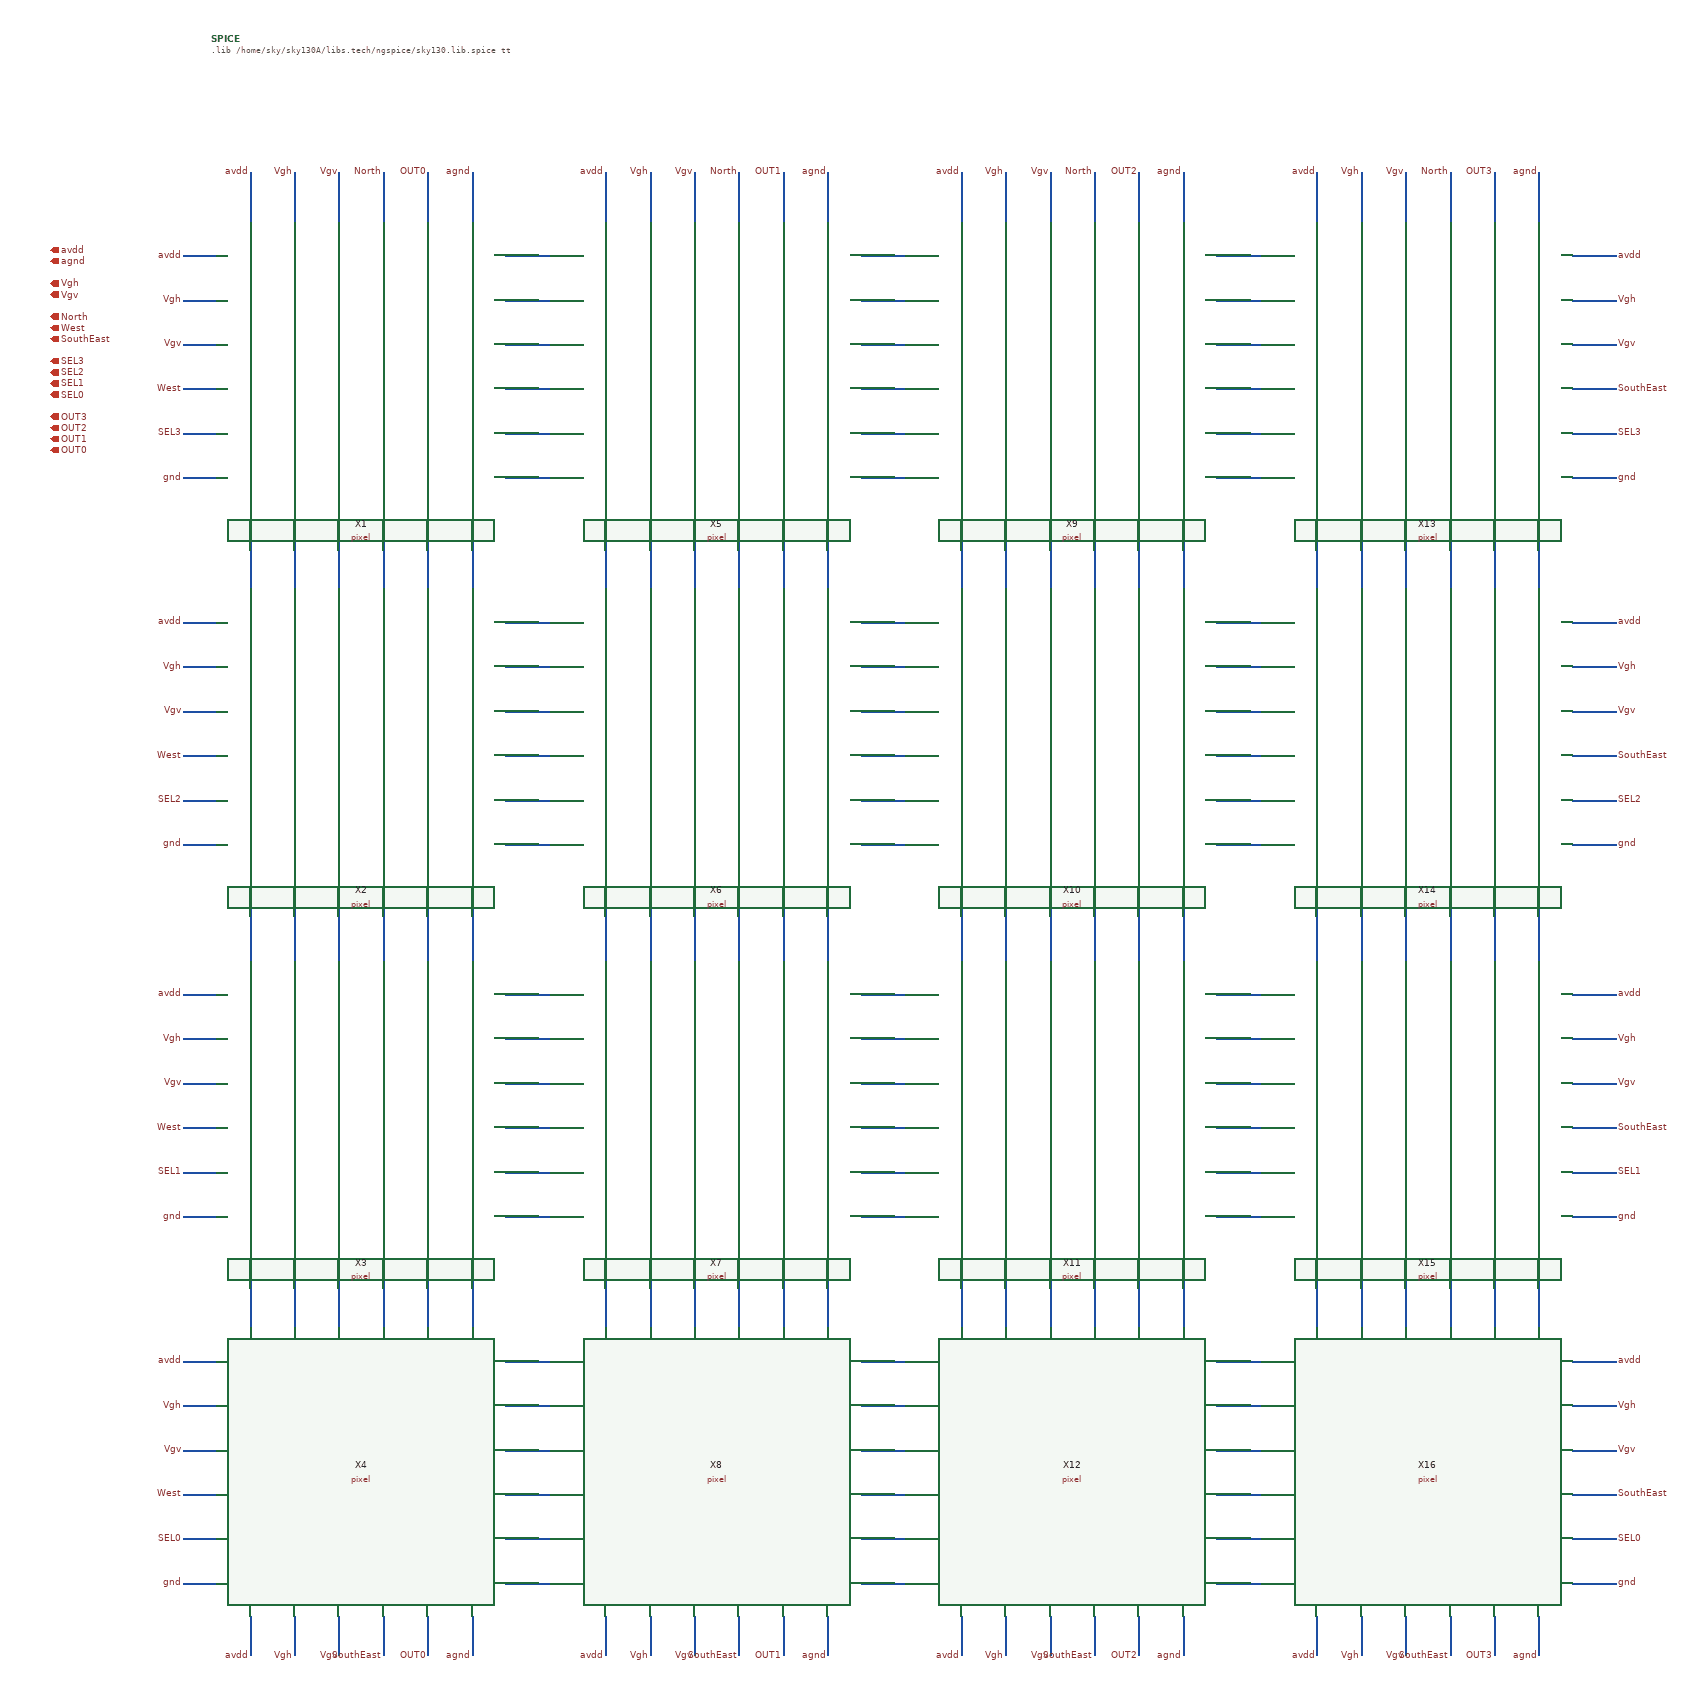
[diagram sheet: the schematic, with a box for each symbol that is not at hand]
v {xschem version=2.9.9 file_version=1.2 }
G {}
K {}
V {}
S {}
E {}
N -1280 -1190 -1220 -1190 { lab=avdd}
N -1280 -1110 -1220 -1110 { lab=Vgh}
N -1280 -1030 -1220 -1030 { lab=Vgv}
N -1160 -1340 -1160 -1250 { lab=avdd}
N -1080 -1340 -1080 -1250 { lab=Vgh}
N -1000 -1340 -1000 -1250 { lab=Vgv}
N -920 -1340 -920 -1250 { lab=North}
N -840 -1340 -840 -1250 { lab=OUT0}
N -760 -1340 -760 -1250 { lab=agnd}
N -700 -1190 -620 -1190 { lab=#net1}
N -700 -1110 -620 -1110 { lab=#net2}
N -700 -1030 -620 -1030 { lab=#net3}
N -700 -950 -620 -950 { lab=#net4}
N -700 -870 -620 -870 { lab=#net5}
N -700 -790 -620 -790 { lab=#net6}
N -760 -730 -760 -660 { lab=#net7}
N -840 -730 -840 -660 { lab=#net8}
N -920 -730 -920 -660 { lab=#net9}
N -1000 -730 -1000 -660 { lab=#net10}
N -1080 -730 -1080 -660 { lab=#net11}
N -1160 -730 -1160 -660 { lab=#net12}
N -1280 -950 -1220 -950 { lab=West}
N -1280 -870 -1220 -870 { lab=SEL3}
N -1280 -790 -1220 -790 { lab=gnd}
N -1280 -530 -1220 -530 { lab=avdd}
N -1280 -450 -1220 -450 { lab=Vgh}
N -1280 -370 -1220 -370 { lab=Vgv}
N -1160 -680 -1160 -590 { lab=#net12}
N -1080 -680 -1080 -590 { lab=#net11}
N -1000 -680 -1000 -590 { lab=#net10}
N -920 -680 -920 -590 { lab=#net9}
N -840 -680 -840 -590 { lab=#net8}
N -760 -680 -760 -590 { lab=#net7}
N -700 -530 -620 -530 { lab=#net13}
N -700 -450 -620 -450 { lab=#net14}
N -700 -370 -620 -370 { lab=#net15}
N -700 -290 -620 -290 { lab=#net16}
N -700 -210 -620 -210 { lab=#net17}
N -700 -130 -620 -130 { lab=#net18}
N -760 -70 -760 0 { lab=#net19}
N -840 -70 -840 0 { lab=#net20}
N -920 -70 -920 0 { lab=#net21}
N -1000 -70 -1000 0 { lab=#net22}
N -1080 -70 -1080 0 { lab=#net23}
N -1160 -70 -1160 0 { lab=#net24}
N -1280 -290 -1220 -290 { lab=West}
N -1280 -210 -1220 -210 { lab=SEL2}
N -1280 -130 -1220 -130 { lab=gnd}
N -1280 140 -1220 140 { lab=avdd}
N -1280 220 -1220 220 { lab=Vgh}
N -1280 300 -1220 300 { lab=Vgv}
N -1160 -10 -1160 80 { lab=#net24}
N -1080 -10 -1080 80 { lab=#net23}
N -1000 -10 -1000 80 { lab=#net22}
N -920 -10 -920 80 { lab=#net21}
N -840 -10 -840 80 { lab=#net20}
N -760 -10 -760 80 { lab=#net19}
N -700 140 -620 140 { lab=#net25}
N -700 220 -620 220 { lab=#net26}
N -700 300 -620 300 { lab=#net27}
N -700 380 -620 380 { lab=#net28}
N -700 460 -620 460 { lab=#net29}
N -700 540 -620 540 { lab=#net30}
N -760 600 -760 670 { lab=#net31}
N -840 600 -840 670 { lab=#net32}
N -920 600 -920 670 { lab=#net33}
N -1000 600 -1000 670 { lab=#net34}
N -1080 600 -1080 670 { lab=#net35}
N -1160 600 -1160 670 { lab=#net36}
N -1280 380 -1220 380 { lab=West}
N -1280 460 -1220 460 { lab=SEL1}
N -1280 540 -1220 540 { lab=gnd}
N -1280 800 -1220 800 { lab=avdd}
N -1280 880 -1220 880 { lab=Vgh}
N -1280 960 -1220 960 { lab=Vgv}
N -1160 650 -1160 740 { lab=#net36}
N -1080 650 -1080 740 { lab=#net35}
N -1000 650 -1000 740 { lab=#net34}
N -920 650 -920 740 { lab=#net33}
N -840 650 -840 740 { lab=#net32}
N -760 650 -760 740 { lab=#net31}
N -700 800 -620 800 { lab=#net37}
N -700 880 -620 880 { lab=#net38}
N -700 960 -620 960 { lab=#net39}
N -700 1040 -620 1040 { lab=#net40}
N -700 1120 -620 1120 { lab=#net41}
N -700 1200 -620 1200 { lab=#net42}
N -760 1260 -760 1330 { lab=agnd}
N -840 1260 -840 1330 { lab=OUT0}
N -920 1260 -920 1330 { lab=SouthEast}
N -1000 1260 -1000 1330 { lab=Vgv}
N -1080 1260 -1080 1330 { lab=Vgh}
N -1160 1260 -1160 1330 { lab=avdd}
N -1280 1040 -1220 1040 { lab=West}
N -1280 1120 -1220 1120 { lab=SEL0}
N -1280 1200 -1220 1200 { lab=gnd}
N -640 -1190 -580 -1190 { lab=#net1}
N -640 -1110 -580 -1110 { lab=#net2}
N -640 -1030 -580 -1030 { lab=#net3}
N -520 -1340 -520 -1250 { lab=avdd}
N -440 -1340 -440 -1250 { lab=Vgh}
N -360 -1340 -360 -1250 { lab=Vgv}
N -280 -1340 -280 -1250 { lab=North}
N -200 -1340 -200 -1250 { lab=OUT1}
N -120 -1340 -120 -1250 { lab=agnd}
N -60 -1190 20 -1190 { lab=#net43}
N -60 -1110 20 -1110 { lab=#net44}
N -60 -1030 20 -1030 { lab=#net45}
N -60 -950 20 -950 { lab=#net46}
N -60 -870 20 -870 { lab=#net47}
N -60 -790 20 -790 { lab=#net48}
N -120 -730 -120 -660 { lab=#net49}
N -200 -730 -200 -660 { lab=#net50}
N -280 -730 -280 -660 { lab=#net51}
N -360 -730 -360 -660 { lab=#net52}
N -440 -730 -440 -660 { lab=#net53}
N -520 -730 -520 -660 { lab=#net54}
N -640 -950 -580 -950 { lab=#net4}
N -640 -870 -580 -870 { lab=#net5}
N -640 -790 -580 -790 { lab=#net6}
N -640 -530 -580 -530 { lab=#net13}
N -640 -450 -580 -450 { lab=#net14}
N -640 -370 -580 -370 { lab=#net15}
N -520 -680 -520 -590 { lab=#net54}
N -440 -680 -440 -590 { lab=#net53}
N -360 -680 -360 -590 { lab=#net52}
N -280 -680 -280 -590 { lab=#net51}
N -200 -680 -200 -590 { lab=#net50}
N -120 -680 -120 -590 { lab=#net49}
N -60 -530 20 -530 { lab=#net55}
N -60 -450 20 -450 { lab=#net56}
N -60 -370 20 -370 { lab=#net57}
N -60 -290 20 -290 { lab=#net58}
N -60 -210 20 -210 { lab=#net59}
N -60 -130 20 -130 { lab=#net60}
N -120 -70 -120 0 { lab=#net61}
N -200 -70 -200 0 { lab=#net62}
N -280 -70 -280 0 { lab=#net63}
N -360 -70 -360 0 { lab=#net64}
N -440 -70 -440 0 { lab=#net65}
N -520 -70 -520 0 { lab=#net66}
N -640 -290 -580 -290 { lab=#net16}
N -640 -210 -580 -210 { lab=#net17}
N -640 -130 -580 -130 { lab=#net18}
N -640 140 -580 140 { lab=#net25}
N -640 220 -580 220 { lab=#net26}
N -640 300 -580 300 { lab=#net27}
N -520 -10 -520 80 { lab=#net66}
N -440 -10 -440 80 { lab=#net65}
N -360 -10 -360 80 { lab=#net64}
N -280 -10 -280 80 { lab=#net63}
N -200 -10 -200 80 { lab=#net62}
N -120 -10 -120 80 { lab=#net61}
N -60 140 20 140 { lab=#net67}
N -60 220 20 220 { lab=#net68}
N -60 300 20 300 { lab=#net69}
N -60 380 20 380 { lab=#net70}
N -60 460 20 460 { lab=#net71}
N -60 540 20 540 { lab=#net72}
N -120 600 -120 670 { lab=#net73}
N -200 600 -200 670 { lab=#net74}
N -280 600 -280 670 { lab=#net75}
N -360 600 -360 670 { lab=#net76}
N -440 600 -440 670 { lab=#net77}
N -520 600 -520 670 { lab=#net78}
N -640 380 -580 380 { lab=#net28}
N -640 460 -580 460 { lab=#net29}
N -640 540 -580 540 { lab=#net30}
N -640 800 -580 800 { lab=#net37}
N -640 880 -580 880 { lab=#net38}
N -640 960 -580 960 { lab=#net39}
N -520 650 -520 740 { lab=#net78}
N -440 650 -440 740 { lab=#net77}
N -360 650 -360 740 { lab=#net76}
N -280 650 -280 740 { lab=#net75}
N -200 650 -200 740 { lab=#net74}
N -120 650 -120 740 { lab=#net73}
N -60 800 20 800 { lab=#net79}
N -60 880 20 880 { lab=#net80}
N -60 960 20 960 { lab=#net81}
N -60 1040 20 1040 { lab=#net82}
N -60 1120 20 1120 { lab=#net83}
N -60 1200 20 1200 { lab=#net84}
N -120 1260 -120 1330 { lab=agnd}
N -200 1260 -200 1330 { lab=OUT1}
N -280 1260 -280 1330 { lab=SouthEast}
N -360 1260 -360 1330 { lab=Vgv}
N -440 1260 -440 1330 { lab=Vgh}
N -520 1260 -520 1330 { lab=avdd}
N -640 1040 -580 1040 { lab=#net40}
N -640 1120 -580 1120 { lab=#net41}
N -640 1200 -580 1200 { lab=#net42}
N 0 -1190 60 -1190 { lab=#net43}
N 0 -1110 60 -1110 { lab=#net44}
N 0 -1030 60 -1030 { lab=#net45}
N 120 -1340 120 -1250 { lab=avdd}
N 200 -1340 200 -1250 { lab=Vgh}
N 280 -1340 280 -1250 { lab=Vgv}
N 360 -1340 360 -1250 { lab=North}
N 440 -1340 440 -1250 { lab=OUT2}
N 520 -1340 520 -1250 { lab=agnd}
N 580 -1190 660 -1190 { lab=#net85}
N 580 -1110 660 -1110 { lab=#net86}
N 580 -1030 660 -1030 { lab=#net87}
N 580 -950 660 -950 { lab=#net88}
N 580 -870 660 -870 { lab=#net89}
N 580 -790 660 -790 { lab=#net90}
N 520 -730 520 -660 { lab=#net91}
N 440 -730 440 -660 { lab=#net92}
N 360 -730 360 -660 { lab=#net93}
N 280 -730 280 -660 { lab=#net94}
N 200 -730 200 -660 { lab=#net95}
N 120 -730 120 -660 { lab=#net96}
N 0 -950 60 -950 { lab=#net46}
N 0 -870 60 -870 { lab=#net47}
N 0 -790 60 -790 { lab=#net48}
N 0 -530 60 -530 { lab=#net55}
N 0 -450 60 -450 { lab=#net56}
N 0 -370 60 -370 { lab=#net57}
N 120 -680 120 -590 { lab=#net96}
N 200 -680 200 -590 { lab=#net95}
N 280 -680 280 -590 { lab=#net94}
N 360 -680 360 -590 { lab=#net93}
N 440 -680 440 -590 { lab=#net92}
N 520 -680 520 -590 { lab=#net91}
N 580 -530 660 -530 { lab=#net97}
N 580 -450 660 -450 { lab=#net98}
N 580 -370 660 -370 { lab=#net99}
N 580 -290 660 -290 { lab=#net100}
N 580 -210 660 -210 { lab=#net101}
N 580 -130 660 -130 { lab=#net102}
N 520 -70 520 0 { lab=#net103}
N 440 -70 440 0 { lab=#net104}
N 360 -70 360 0 { lab=#net105}
N 280 -70 280 0 { lab=#net106}
N 200 -70 200 0 { lab=#net107}
N 120 -70 120 0 { lab=#net108}
N 0 -290 60 -290 { lab=#net58}
N 0 -210 60 -210 { lab=#net59}
N 0 -130 60 -130 { lab=#net60}
N 0 140 60 140 { lab=#net67}
N 0 220 60 220 { lab=#net68}
N 0 300 60 300 { lab=#net69}
N 120 -10 120 80 { lab=#net108}
N 200 -10 200 80 { lab=#net107}
N 280 -10 280 80 { lab=#net106}
N 360 -10 360 80 { lab=#net105}
N 440 -10 440 80 { lab=#net104}
N 520 -10 520 80 { lab=#net103}
N 580 140 660 140 { lab=#net109}
N 580 220 660 220 { lab=#net110}
N 580 300 660 300 { lab=#net111}
N 580 380 660 380 { lab=#net112}
N 580 460 660 460 { lab=#net113}
N 580 540 660 540 { lab=#net114}
N 520 600 520 670 { lab=#net115}
N 440 600 440 670 { lab=#net116}
N 360 600 360 670 { lab=#net117}
N 280 600 280 670 { lab=#net118}
N 200 600 200 670 { lab=#net119}
N 120 600 120 670 { lab=#net120}
N 0 380 60 380 { lab=#net70}
N 0 460 60 460 { lab=#net71}
N 0 540 60 540 { lab=#net72}
N 0 800 60 800 { lab=#net79}
N 0 880 60 880 { lab=#net80}
N 0 960 60 960 { lab=#net81}
N 120 650 120 740 { lab=#net120}
N 200 650 200 740 { lab=#net119}
N 280 650 280 740 { lab=#net118}
N 360 650 360 740 { lab=#net117}
N 440 650 440 740 { lab=#net116}
N 520 650 520 740 { lab=#net115}
N 580 800 660 800 { lab=#net121}
N 580 880 660 880 { lab=#net122}
N 580 960 660 960 { lab=#net123}
N 580 1040 660 1040 { lab=#net124}
N 580 1120 660 1120 { lab=#net125}
N 580 1200 660 1200 { lab=#net126}
N 520 1260 520 1330 { lab=agnd}
N 440 1260 440 1330 { lab=OUT2}
N 360 1260 360 1330 { lab=SouthEast}
N 280 1260 280 1330 { lab=Vgv}
N 200 1260 200 1330 { lab=Vgh}
N 120 1260 120 1330 { lab=avdd}
N 0 1040 60 1040 { lab=#net82}
N 0 1120 60 1120 { lab=#net83}
N 0 1200 60 1200 { lab=#net84}
N 640 -1190 700 -1190 { lab=#net85}
N 640 -1110 700 -1110 { lab=#net86}
N 640 -1030 700 -1030 { lab=#net87}
N 760 -1340 760 -1250 { lab=avdd}
N 840 -1340 840 -1250 { lab=Vgh}
N 920 -1340 920 -1250 { lab=Vgv}
N 1000 -1340 1000 -1250 { lab=North}
N 1080 -1340 1080 -1250 { lab=OUT3}
N 1160 -1340 1160 -1250 { lab=agnd}
N 1220 -1190 1300 -1190 { lab=avdd}
N 1220 -1110 1300 -1110 { lab=Vgh}
N 1220 -1030 1300 -1030 { lab=Vgv}
N 1220 -950 1300 -950 { lab=#net127}
N 1220 -870 1300 -870 { lab=SEL3}
N 1220 -790 1300 -790 { lab=gnd}
N 1160 -730 1160 -660 { lab=#net128}
N 1080 -730 1080 -660 { lab=#net129}
N 1000 -730 1000 -660 { lab=#net130}
N 920 -730 920 -660 { lab=#net131}
N 840 -730 840 -660 { lab=#net132}
N 760 -730 760 -660 { lab=#net133}
N 640 -950 700 -950 { lab=#net88}
N 640 -870 700 -870 { lab=#net89}
N 640 -790 700 -790 { lab=#net90}
N 640 -530 700 -530 { lab=#net97}
N 640 -450 700 -450 { lab=#net98}
N 640 -370 700 -370 { lab=#net99}
N 760 -680 760 -590 { lab=#net133}
N 840 -680 840 -590 { lab=#net132}
N 920 -680 920 -590 { lab=#net131}
N 1000 -680 1000 -590 { lab=#net130}
N 1080 -680 1080 -590 { lab=#net129}
N 1160 -680 1160 -590 { lab=#net128}
N 1220 -530 1300 -530 { lab=avdd}
N 1220 -450 1300 -450 { lab=Vgh}
N 1220 -370 1300 -370 { lab=Vgv}
N 1220 -290 1300 -290 { lab=SouthEast}
N 1220 -210 1300 -210 { lab=SEL2}
N 1220 -130 1300 -130 { lab=gnd}
N 1160 -70 1160 0 { lab=#net134}
N 1080 -70 1080 0 { lab=#net135}
N 1000 -70 1000 0 { lab=#net136}
N 920 -70 920 0 { lab=#net137}
N 840 -70 840 0 { lab=#net138}
N 760 -70 760 0 { lab=#net139}
N 640 -290 700 -290 { lab=#net100}
N 640 -210 700 -210 { lab=#net101}
N 640 -130 700 -130 { lab=#net102}
N 640 140 700 140 { lab=#net109}
N 640 220 700 220 { lab=#net110}
N 640 300 700 300 { lab=#net111}
N 760 -10 760 80 { lab=#net139}
N 840 -10 840 80 { lab=#net138}
N 920 -10 920 80 { lab=#net137}
N 1000 -10 1000 80 { lab=#net136}
N 1080 -10 1080 80 { lab=#net135}
N 1160 -10 1160 80 { lab=#net134}
N 1220 140 1300 140 { lab=avdd}
N 1220 220 1300 220 { lab=Vgh}
N 1220 300 1300 300 { lab=Vgv}
N 1220 380 1300 380 { lab=SouthEast}
N 1220 460 1300 460 { lab=SEL1}
N 1220 540 1300 540 { lab=gnd}
N 1160 600 1160 670 { lab=#net140}
N 1080 600 1080 670 { lab=#net141}
N 1000 600 1000 670 { lab=#net142}
N 920 600 920 670 { lab=#net143}
N 840 600 840 670 { lab=#net144}
N 760 600 760 670 { lab=#net145}
N 640 380 700 380 { lab=#net112}
N 640 460 700 460 { lab=#net113}
N 640 540 700 540 { lab=#net114}
N 640 800 700 800 { lab=#net121}
N 640 880 700 880 { lab=#net122}
N 640 960 700 960 { lab=#net123}
N 760 650 760 740 { lab=#net145}
N 840 650 840 740 { lab=#net144}
N 920 650 920 740 { lab=#net143}
N 1000 650 1000 740 { lab=#net142}
N 1080 650 1080 740 { lab=#net141}
N 1160 650 1160 740 { lab=#net140}
N 1220 800 1300 800 { lab=avdd}
N 1220 880 1300 880 { lab=Vgh}
N 1220 960 1300 960 { lab=Vgv}
N 1220 1040 1300 1040 { lab=SouthEast}
N 1220 1120 1300 1120 { lab=SEL0}
N 1220 1200 1300 1200 { lab=gnd}
N 1160 1260 1160 1330 { lab=agnd}
N 1080 1260 1080 1330 { lab=OUT3}
N 1000 1260 1000 1330 { lab=SouthEast}
N 920 1260 920 1330 { lab=Vgv}
N 840 1260 840 1330 { lab=Vgh}
N 760 1260 760 1330 { lab=avdd}
N 640 1040 700 1040 { lab=#net124}
N 640 1120 700 1120 { lab=#net125}
N 640 1200 700 1200 { lab=#net126}
C {devices/netlist.sym} -1230 -1580 0 0 {name=SPICE only_toplevel=false value="
.lib /home/sky/sky130A/libs.tech/ngspice/sky130.lib.spice tt
"}
C {HW4_RAM_readout/pixel.sym} -960 -990 0 0 {name=X1}
C {HW4_RAM_readout/pixel.sym} -960 -330 0 0 {name=X2}
C {HW4_RAM_readout/pixel.sym} -960 340 0 0 {name=X3}
C {HW4_RAM_readout/pixel.sym} -960 1000 0 0 {name=X4}
C {HW4_RAM_readout/pixel.sym} -320 -990 0 0 {name=X5}
C {HW4_RAM_readout/pixel.sym} -320 -330 0 0 {name=X6}
C {HW4_RAM_readout/pixel.sym} -320 340 0 0 {name=X7}
C {HW4_RAM_readout/pixel.sym} -320 1000 0 0 {name=X8}
C {HW4_RAM_readout/pixel.sym} 320 -990 0 0 {name=X9}
C {HW4_RAM_readout/pixel.sym} 320 -330 0 0 {name=X10}
C {HW4_RAM_readout/pixel.sym} 320 340 0 0 {name=X11}
C {HW4_RAM_readout/pixel.sym} 320 1000 0 0 {name=X12}
C {HW4_RAM_readout/pixel.sym} 960 -990 0 0 {name=X13}
C {HW4_RAM_readout/pixel.sym} 960 -330 0 0 {name=X14}
C {HW4_RAM_readout/pixel.sym} 960 340 0 0 {name=X15}
C {HW4_RAM_readout/pixel.sym} 960 1000 0 0 {name=X16}
C {devices/iopin.sym} -1520 -1200 0 1 {name=p2 lab=avdd}
C {devices/iopin.sym} -1520 -1140 0 1 {name=p6 lab=Vgh}
C {devices/iopin.sym} -1520 -1120 0 1 {name=p7 lab=Vgv}
C {devices/iopin.sym} -1520 -1080 0 1 {name=p8 lab=North}
C {devices/iopin.sym} -1520 -840 0 1 {name=p9 lab=OUT0}
C {devices/iopin.sym} -1520 -1180 0 1 {name=p10 lab=agnd}
C {devices/iopin.sym} -1520 -860 0 1 {name=p12 lab=OUT1}
C {devices/iopin.sym} -1520 -880 0 1 {name=p18 lab=OUT2}
C {devices/iopin.sym} -1520 -900 0 1 {name=p24 lab=OUT3}
C {devices/iopin.sym} -1520 -1060 0 1 {name=p53 lab=West}
C {devices/iopin.sym} -1520 -1000 0 1 {name=p54 lab=SEL3}
C {devices/iopin.sym} -1520 -980 0 1 {name=p60 lab=SEL2}
C {devices/iopin.sym} -1520 -960 0 1 {name=p66 lab=SEL1}
C {devices/iopin.sym} -1520 -940 0 1 {name=p72 lab=SEL0}
C {devices/lab_pin.sym} 1300 -1190 0 1 {name=l35 sig_type=std_logic lab=avdd}
C {devices/lab_pin.sym} 1300 -1110 0 1 {name=l36 sig_type=std_logic lab=Vgh}
C {devices/lab_pin.sym} 1300 -1030 0 1 {name=l37 sig_type=std_logic lab=Vgv}
C {devices/lab_pin.sym} 1300 -790 0 1 {name=l38 sig_type=std_logic lab=gnd}
C {devices/lab_pin.sym} 1300 -530 0 1 {name=l39 sig_type=std_logic lab=avdd}
C {devices/lab_pin.sym} 1300 -450 0 1 {name=l40 sig_type=std_logic lab=Vgh}
C {devices/lab_pin.sym} 1300 -370 0 1 {name=l41 sig_type=std_logic lab=Vgv}
C {devices/lab_pin.sym} 1300 -130 0 1 {name=l42 sig_type=std_logic lab=gnd}
C {devices/lab_pin.sym} 1300 -290 0 1 {name=l43 sig_type=std_logic lab=SouthEast}
C {devices/lab_pin.sym} 1300 140 0 1 {name=l44 sig_type=std_logic lab=avdd}
C {devices/lab_pin.sym} 1300 220 0 1 {name=l45 sig_type=std_logic lab=Vgh}
C {devices/lab_pin.sym} 1300 300 0 1 {name=l46 sig_type=std_logic lab=Vgv}
C {devices/lab_pin.sym} 1300 540 0 1 {name=l47 sig_type=std_logic lab=gnd}
C {devices/lab_pin.sym} 1300 380 0 1 {name=l48 sig_type=std_logic lab=SouthEast}
C {devices/lab_pin.sym} 1300 800 0 1 {name=l49 sig_type=std_logic lab=avdd}
C {devices/lab_pin.sym} 1300 880 0 1 {name=l50 sig_type=std_logic lab=Vgh}
C {devices/lab_pin.sym} 1300 960 0 1 {name=l51 sig_type=std_logic lab=Vgv}
C {devices/lab_pin.sym} 1300 1200 0 1 {name=l52 sig_type=std_logic lab=gnd}
C {devices/lab_pin.sym} 1300 1040 0 1 {name=l53 sig_type=std_logic lab=SouthEast}
C {devices/lab_pin.sym} 760 1330 1 1 {name=l64 sig_type=std_logic lab=avdd}
C {devices/lab_pin.sym} 840 1330 1 1 {name=l65 sig_type=std_logic lab=Vgh}
C {devices/lab_pin.sym} 920 1330 1 1 {name=l66 sig_type=std_logic lab=Vgv}
C {devices/lab_pin.sym} 1000 1330 1 1 {name=l67 sig_type=std_logic lab=SouthEast}
C {devices/lab_pin.sym} 1160 1330 1 1 {name=l68 sig_type=std_logic lab=agnd}
C {devices/lab_pin.sym} 1300 -870 0 1 {name=l69 sig_type=std_logic lab=SEL3}
C {devices/lab_pin.sym} 1300 -210 0 1 {name=l70 sig_type=std_logic lab=SEL2}
C {devices/lab_pin.sym} 1300 460 0 1 {name=l71 sig_type=std_logic lab=SEL1}
C {devices/lab_pin.sym} 1300 1120 0 1 {name=l72 sig_type=std_logic lab=SEL0}
C {devices/lab_pin.sym} 1080 1330 1 1 {name=l73 sig_type=std_logic lab=OUT3}
C {devices/lab_pin.sym} 120 1330 1 1 {name=l59 sig_type=std_logic lab=avdd}
C {devices/lab_pin.sym} 200 1330 1 1 {name=l60 sig_type=std_logic lab=Vgh}
C {devices/lab_pin.sym} 280 1330 1 1 {name=l61 sig_type=std_logic lab=Vgv}
C {devices/lab_pin.sym} 360 1330 1 1 {name=l62 sig_type=std_logic lab=SouthEast}
C {devices/lab_pin.sym} 520 1330 1 1 {name=l63 sig_type=std_logic lab=agnd}
C {devices/lab_pin.sym} 440 1330 1 1 {name=l74 sig_type=std_logic lab=OUT2}
C {devices/lab_pin.sym} -520 1330 1 1 {name=l54 sig_type=std_logic lab=avdd}
C {devices/lab_pin.sym} -440 1330 1 1 {name=l55 sig_type=std_logic lab=Vgh}
C {devices/lab_pin.sym} -360 1330 1 1 {name=l56 sig_type=std_logic lab=Vgv}
C {devices/lab_pin.sym} -280 1330 1 1 {name=l57 sig_type=std_logic lab=SouthEast}
C {devices/lab_pin.sym} -120 1330 1 1 {name=l58 sig_type=std_logic lab=agnd}
C {devices/lab_pin.sym} -200 1330 1 1 {name=l75 sig_type=std_logic lab=OUT1}
C {devices/lab_pin.sym} -1160 1330 1 1 {name=l76 sig_type=std_logic lab=avdd}
C {devices/lab_pin.sym} -1080 1330 1 1 {name=l77 sig_type=std_logic lab=Vgh}
C {devices/lab_pin.sym} -1000 1330 1 1 {name=l78 sig_type=std_logic lab=Vgv}
C {devices/lab_pin.sym} -920 1330 1 1 {name=l79 sig_type=std_logic lab=SouthEast}
C {devices/lab_pin.sym} -760 1330 1 1 {name=l80 sig_type=std_logic lab=agnd}
C {devices/lab_pin.sym} -840 1330 1 1 {name=l81 sig_type=std_logic lab=OUT0}
C {devices/lab_pin.sym} 760 -1340 1 0 {name=l82 sig_type=std_logic lab=avdd}
C {devices/lab_pin.sym} 840 -1340 1 0 {name=l83 sig_type=std_logic lab=Vgh}
C {devices/lab_pin.sym} 920 -1340 1 0 {name=l84 sig_type=std_logic lab=Vgv}
C {devices/lab_pin.sym} 1160 -1340 1 0 {name=l86 sig_type=std_logic lab=agnd}
C {devices/lab_pin.sym} 1080 -1340 1 0 {name=l87 sig_type=std_logic lab=OUT3}
C {devices/lab_pin.sym} 120 -1340 1 0 {name=l88 sig_type=std_logic lab=avdd}
C {devices/lab_pin.sym} 200 -1340 1 0 {name=l89 sig_type=std_logic lab=Vgh}
C {devices/lab_pin.sym} 280 -1340 1 0 {name=l90 sig_type=std_logic lab=Vgv}
C {devices/lab_pin.sym} 520 -1340 1 0 {name=l92 sig_type=std_logic lab=agnd}
C {devices/lab_pin.sym} 440 -1340 1 0 {name=l93 sig_type=std_logic lab=OUT2}
C {devices/lab_pin.sym} -520 -1340 1 0 {name=l94 sig_type=std_logic lab=avdd}
C {devices/lab_pin.sym} -440 -1340 1 0 {name=l95 sig_type=std_logic lab=Vgh}
C {devices/lab_pin.sym} -360 -1340 1 0 {name=l96 sig_type=std_logic lab=Vgv}
C {devices/lab_pin.sym} -280 -1340 1 0 {name=l97 sig_type=std_logic lab=North}
C {devices/lab_pin.sym} -120 -1340 1 0 {name=l98 sig_type=std_logic lab=agnd}
C {devices/lab_pin.sym} -200 -1340 1 0 {name=l99 sig_type=std_logic lab=OUT1}
C {devices/lab_pin.sym} -1160 -1340 1 0 {name=l100 sig_type=std_logic lab=avdd}
C {devices/lab_pin.sym} -1080 -1340 1 0 {name=l101 sig_type=std_logic lab=Vgh}
C {devices/lab_pin.sym} -1000 -1340 1 0 {name=l102 sig_type=std_logic lab=Vgv}
C {devices/lab_pin.sym} -920 -1340 1 0 {name=l103 sig_type=std_logic lab=North}
C {devices/lab_pin.sym} -760 -1340 1 0 {name=l104 sig_type=std_logic lab=agnd}
C {devices/lab_pin.sym} -840 -1340 1 0 {name=l105 sig_type=std_logic lab=OUT0}
C {devices/lab_pin.sym} -1280 -1190 0 0 {name=l1 sig_type=std_logic lab=avdd}
C {devices/lab_pin.sym} -1280 -1110 0 0 {name=l2 sig_type=std_logic lab=Vgh}
C {devices/lab_pin.sym} -1280 -1030 0 0 {name=l3 sig_type=std_logic lab=Vgv}
C {devices/lab_pin.sym} -1280 -790 0 0 {name=l4 sig_type=std_logic lab=gnd}
C {devices/lab_pin.sym} -1280 -530 0 0 {name=l5 sig_type=std_logic lab=avdd}
C {devices/lab_pin.sym} -1280 -450 0 0 {name=l6 sig_type=std_logic lab=Vgh}
C {devices/lab_pin.sym} -1280 -370 0 0 {name=l7 sig_type=std_logic lab=Vgv}
C {devices/lab_pin.sym} -1280 -130 0 0 {name=l8 sig_type=std_logic lab=gnd}
C {devices/lab_pin.sym} -1280 140 0 0 {name=l10 sig_type=std_logic lab=avdd}
C {devices/lab_pin.sym} -1280 220 0 0 {name=l11 sig_type=std_logic lab=Vgh}
C {devices/lab_pin.sym} -1280 300 0 0 {name=l12 sig_type=std_logic lab=Vgv}
C {devices/lab_pin.sym} -1280 540 0 0 {name=l13 sig_type=std_logic lab=gnd}
C {devices/lab_pin.sym} -1280 800 0 0 {name=l15 sig_type=std_logic lab=avdd}
C {devices/lab_pin.sym} -1280 880 0 0 {name=l16 sig_type=std_logic lab=Vgh}
C {devices/lab_pin.sym} -1280 960 0 0 {name=l17 sig_type=std_logic lab=Vgv}
C {devices/lab_pin.sym} -1280 1200 0 0 {name=l18 sig_type=std_logic lab=gnd}
C {devices/lab_pin.sym} -1280 -870 0 0 {name=l20 sig_type=std_logic lab=SEL3}
C {devices/lab_pin.sym} -1280 -210 0 0 {name=l21 sig_type=std_logic lab=SEL2}
C {devices/lab_pin.sym} -1280 460 0 0 {name=l22 sig_type=std_logic lab=SEL1}
C {devices/lab_pin.sym} -1280 1120 0 0 {name=l23 sig_type=std_logic lab=SEL0}
C {devices/lab_pin.sym} -1280 -950 0 0 {name=l24 sig_type=std_logic lab=West}
C {devices/lab_pin.sym} -1280 -290 0 0 {name=l9 sig_type=std_logic lab=West}
C {devices/lab_pin.sym} -1280 380 0 0 {name=l14 sig_type=std_logic lab=West}
C {devices/lab_pin.sym} -1280 1040 0 0 {name=l19 sig_type=std_logic lab=West}
C {devices/lab_pin.sym} 360 -1340 1 0 {name=l25 sig_type=std_logic lab=North}
C {devices/lab_pin.sym} 1000 -1340 1 0 {name=l26 sig_type=std_logic lab=North}
C {devices/iopin.sym} -1520 -1040 0 1 {name=p1 lab=SouthEast}
C {devices/lab_pin.sym} 1300 -950 0 1 {name=l27 sig_type=std_logic lab=SouthEast}
